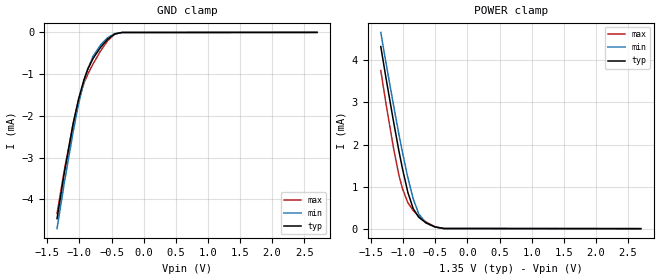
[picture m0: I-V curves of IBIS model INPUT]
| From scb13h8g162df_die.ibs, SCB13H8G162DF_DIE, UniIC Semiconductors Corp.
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|   Model INPUT
[Model] INPUT
Model_type Input
Polarity   Non-Inverting
Enable   Active-High
Vinl =  0.550V
Vinh =  0.800V
C_comp   0.556pF   0.548pF   0.561pF
C_comp_power_clamp   0.119pF   0.115pF   0.122pF
C_comp_gnd_clamp   0.437pF   0.433pF   0.439pF
[Temperature Range]   45.000   95.000   -40.000
[Voltage Range]   1.350V   1.283V   1.425V
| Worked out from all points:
|   GND clamp passes 1 mA (typ) near -0.90 V on its own axis
|   POWER clamp passes 1 mA (typ) near -0.95 V on its own axis
[GND_clamp]
|Voltage   I(typ)   I(min)   I(max)
-1.35V    -4.459mA   -4.699mA   -4.332mA
-1.238V   -3.374mA   -3.617mA   -3.314mA
-1.097V   -2.175mA   -2.364mA   -2.167mA
-1.013V   -1.587mA   -1.704mA   -1.607mA
-928mV    -1.122mA   -1.16mA    -1.204mA
-872mV    -885.7uA   -877.9uA   -1.006mA
-788mV    -622.5uA   -570.5uA   -752.1uA
-675mV    -364.9uA   -305.9uA   -453.3uA
-563mV    -165.4uA   -128.1uA   -202.9uA
-450mV    -38.09uA   -27.42uA   -40.32uA
-338mV    -2.553uA   -2.201uA   -1.39uA
2.7V      0A         0A         0A
[POWER_clamp]
|Voltage   I(typ)   I(min)   I(max)
-1.35V    4.331mA    4.667mA    3.761mA
-1.266V   3.557mA    3.918mA    2.946mA
-1.153V   2.561mA    2.949mA    1.928mA
-1.069V   1.859mA    2.255mA    1.281mA
-1.012V   1.425mA    1.815mA    950.8uA
-928mV    862.1uA    1.21mA     617uA
-844mV    472.4uA    705.3uA    428.3uA
-759mV    272.3uA    354.4uA    298.8uA
-647mV    139.8uA    137.3uA    161uA
-506mV    42.4uA     36.88uA    42.07uA
-366mV    3.748uA    3.583uA    1.942uA
2.7V      0A         0A         0A
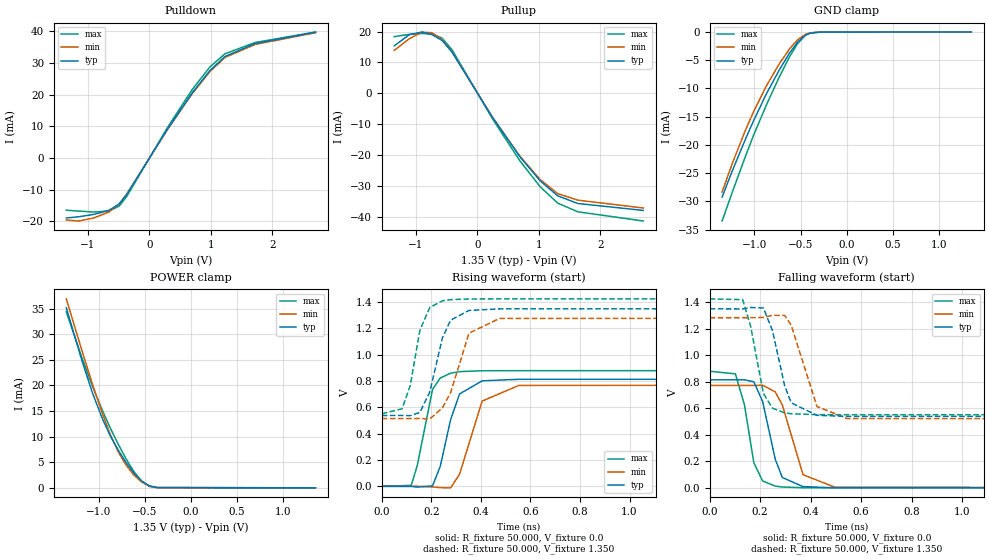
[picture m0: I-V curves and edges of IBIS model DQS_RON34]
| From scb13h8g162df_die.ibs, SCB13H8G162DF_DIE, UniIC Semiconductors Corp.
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|   Model DQS_RON34
[Model] DQS_RON34
Model_type I/O
Polarity   Non-Inverting
Enable   Active-High
Vinl =  0.545V
Vinh =  0.805V
Vmeas =  0.675V
Cref =  0.0F
Rref =  50.000
Vref =  0.675V
C_comp   0.955pF   0.936pF   0.968pF
C_comp_pullup   0.230pF   0.220pF   0.237pF
C_comp_pulldown   0.725pF   0.716pF   0.731pF
[Temperature Range]   45.000   95.000   -40.000
[Voltage Range]   1.350V   1.283V   1.425V
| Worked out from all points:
|   slope of the pulldown table from 0 to 0.203 V, typ, clamps not added: 32.2 ohm
|   slope of the pullup table from 0 to 0.203 V, typ, clamps not added: 31.7 ohm
|   GND clamp passes 1 mA (typ) near -0.48 V on its own axis
|   POWER clamp passes 1 mA (typ) near -0.51 V on its own axis
|   rising waveform, R_fixture 50.000, V_fixture 0.0: 20-80 % time 62.9ps typ, 70.8ps min, 52.9ps max; typ from 0 V to 0.814 V
|   rising waveform, R_fixture 50.000, V_fixture 1.350: 20-80 % time 65.7ps typ, 75.8ps min, 54.2ps max; typ from 0.539 V to 1.35 V
|   falling waveform, R_fixture 50.000, V_fixture 0.0: 20-80 % time 58.1ps typ, 66.1ps min, 48.7ps max; typ from 0.814 V to 0 V
|   falling waveform, R_fixture 50.000, V_fixture 1.350: 20-80 % time 60ps typ, 67.7ps min, 52ps max; typ from 1.35 V to 0.539 V
[Pulldown]
|Voltage   I(typ)   I(min)   I(max)
-1.35V    -19.01mA   -19.65mA   -16.56mA
-1.145V   -18.62mA   -19.97mA   -16.83mA
-900mV    -17.87mA   -18.99mA   -17.14mA
-655mV    -16.56mA   -17.08mA   -16.79mA
-491mV    -14.58mA   -14.62mA   -15.27mA
-368mV    -11.59mA   -11.44mA   -12.21mA
286mV     8.844mA    8.714mA    9.336mA
695mV     20.54mA    20.28mA    21.58mA
982mV     27.56mA    27.26mA    28.72mA
1.227V    32.07mA    31.76mA    32.93mA
1.718V    36.19mA    35.89mA    36.51mA
2.7V      39.79mA    39.61mA    39.83mA
[Pullup]
|Voltage   I(typ)   I(min)   I(max)
-1.35V    15.36mA    13.9mA     18.35mA
-1.105V   18.99mA    17.66mA    19.08mA
-900mV    19.84mA    19.78mA    19.37mA
-736mV    19mA       19.61mA    19.18mA
-573mV    17.13mA    17.44mA    17.89mA
-409mV    13.34mA    13.36mA    14.07mA
245mV     -7.732mA   -7.686mA   -8.189mA
695mV     -20.62mA   -20.42mA   -21.94mA
1.023V    -28.37mA   -27.97mA   -30.29mA
1.309V    -33.24mA   -32.51mA   -35.61mA
1.636V    -35.71mA   -34.63mA   -38.4mA
2.7V      -37.95mA   -37.16mA   -41.38mA
[GND_clamp]
|Voltage   I(typ)   I(min)   I(max)
-1.35V    -29.26mA   -28.34mA   -33.49mA
-1.238V   -24.53mA   -23.21mA   -28.3mA
-1.097V   -18.99mA   -17.39mA   -22.02mA
-1.013V   -15.85mA   -14.25mA   -18.44mA
-872mV    -11.01mA   -9.597mA   -12.98mA
-731mV    -6.729mA   -5.642mA   -7.982mA
-619mV    -3.711mA   -2.975mA   -4.366mA
-534mV    -1.839mA   -1.403mA   -2.088mA
-450mV    -579.7uA   -428.9uA   -569.3uA
-394mV    -185.5uA   -144.2uA   -144.2uA
-281mV    -9.318uA   -9.811uA   -3.103uA
1.35V     0A         0A         0A
[POWER_clamp]
|Voltage   I(typ)   I(min)   I(max)
-1.35V    35.16mA    36.91mA    34.39mA
-1.181V   24.89mA    26.83mA    25.44mA
-1.069V   18.67mA    20.39mA    19.96mA
-956mV    13.38mA    14.37mA    15mA
-872mV    10.11mA    10.36mA    11.63mA
-787mV    7.358mA    7.025mA    8.526mA
-703mV    4.977mA    4.465mA    5.69mA
-619mV    2.933mA    2.534mA    3.219mA
-534mV    1.338mA    1.137mA    1.316mA
-450mV    385.5uA    342uA      284.3uA
-366mV    62.9uA     66.43uA    27.04uA
1.35V     0A         0A         9.135nA
[Ramp]
| variable   typ   min   max
dV/dt_r   0.489/62.977p   0.463/70.903p   0.528/52.483p
dV/dt_f   0.487/60.040p   0.461/68.197p   0.524/51.945p
R_load = 50.000
[Rising Waveform]
R_fixture= 50.000
V_fixture= 0.0
V_fixture_min= 0.0
V_fixture_max= 0.0
|time   V(typ)   V(min)   V(max)
0s        96.21nV    255.9nV    9.828uV
119ps     -439.2uV   -70.9uV    7.242mV
143ps     -5.912mV   325.2uV    155.7mV
205ps     3.96mV     -4.63mV    737.4mV
236ps     151.3mV    -10.16mV   823mV
278ps     507.5mV    -11.58mV   860.4mV
314ps     702.2mV    92.24mV    871.8mV
405ps     801.8mV    647.9mV    878.6mV
553ps     813.7mV    767.1mV    879.4mV
5ns       814.2mV    772.4mV    879.4mV
[Rising Waveform]
R_fixture= 50.000
V_fixture= 1.350
V_fixture_min= 1.283
V_fixture_max= 1.425
|time   V(typ)   V(min)   V(max)
0s        538.6mV    515.3mV    551.5mV
82ps      538.7mV    515.3mV    589.4mV
115ps     537.1mV    515.3mV    766.7mV
154ps     562mV      515.7mV    1.187V
194ps     718mV      512.2mV    1.36V
245ps     1.13V      597mV      1.41V
278ps     1.263V     712.2mV    1.419V
352ps     1.337V     1.164V     1.424V
475ps     1.349V     1.276V     1.425V
5ns       1.35V      1.283V     1.425V
[Falling Waveform]
R_fixture= 50.000
V_fixture= 0.0
V_fixture_min= 0.0
V_fixture_max= 0.0
|time   V(typ)   V(min)   V(max)
0s        814.2mV    772.4mV    879.4mV
102ps     814.3mV    772.4mV    859.3mV
138ps     814.4mV    772.4mV    625.4mV
175ps     799.5mV    772.1mV    189.7mV
210ps     650.8mV    774.1mV    51.48mV
260ps     214.6mV    723.2mV    13.04mV
288ps     78.18mV    624.5mV    6.39mV
370ps     9.051mV    99.09mV    899.1uV
496ps     564.3uV    4.591mV    47.18uV
5ns       98.67nV    255.9nV    10.17uV
[Falling Waveform]
R_fixture= 50.000
V_fixture= 1.350
V_fixture_min= 1.283
V_fixture_max= 1.425
|time   V(typ)   V(min)   V(max)
0s        1.35V      1.283V     1.425V
131ps     1.349V     1.283V     1.419V
162ps     1.36V      1.283V     1.221V
213ps     1.356V     1.285V     710.9mV
249ps     1.185V     1.301V     601mV
297ps     771.6mV    1.3V       565.3mV
323ps     641.3mV    1.227V     558.6mV
425ps     546.7mV    613.8mV    552mV
543ps     539.3mV    522.9mV    551.5mV
5ns       538.6mV    515.3mV    551.5mV
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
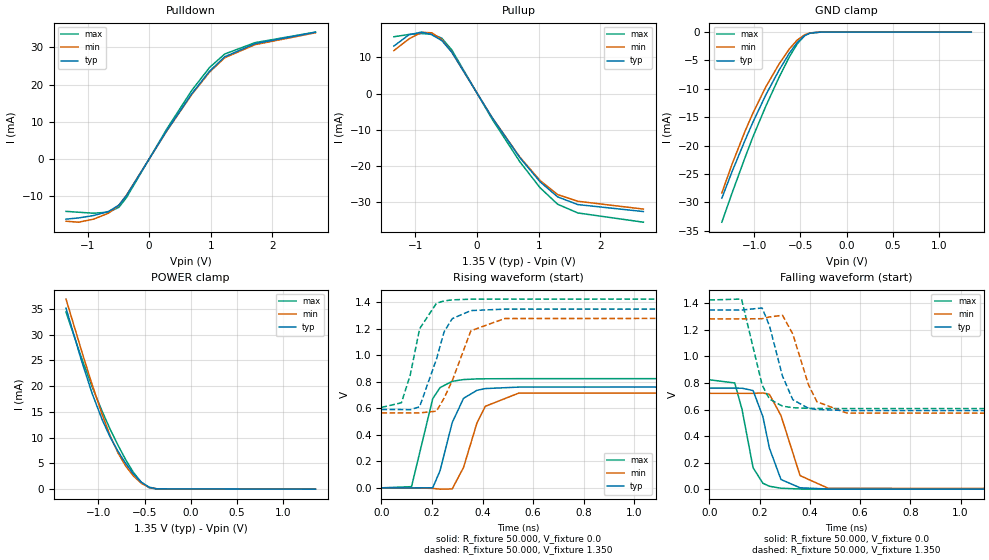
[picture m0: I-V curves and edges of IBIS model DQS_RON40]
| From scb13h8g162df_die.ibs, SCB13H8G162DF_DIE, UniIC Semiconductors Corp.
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|   Model DQS_RON40
[Model] DQS_RON40
Model_type I/O
Polarity   Non-Inverting
Enable   Active-High
Vinl =  0.545V
Vinh =  0.805V
Vmeas =  0.675V
Cref =  0.0F
Rref =  50.000
Vref =  0.675V
C_comp   0.962pF   0.943pF   0.974pF
C_comp_pullup   0.232pF   0.222pF   0.238pF
C_comp_pulldown   0.730pF   0.721pF   0.736pF
[Temperature Range]   45.000   95.000   -40.000
[Voltage Range]   1.350V   1.283V   1.425V
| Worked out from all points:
|   slope of the pulldown table from 0 to 0.203 V, typ, clamps not added: 37.6 ohm
|   slope of the pullup table from 0 to 0.203 V, typ, clamps not added: 36.9 ohm
|   GND clamp passes 1 mA (typ) near -0.48 V on its own axis
|   POWER clamp passes 1 mA (typ) near -0.51 V on its own axis
|   rising waveform, R_fixture 50.000, V_fixture 0.0: 20-80 % time 66.8ps typ, 75.1ps min, 56.5ps max; typ from 0 V to 0.761 V
|   rising waveform, R_fixture 50.000, V_fixture 1.350: 20-80 % time 71.2ps typ, 82.6ps min, 59.3ps max; typ from 0.591 V to 1.35 V
|   falling waveform, R_fixture 50.000, V_fixture 0.0: 20-80 % time 58.8ps typ, 68.9ps min, 50.6ps max; typ from 0.761 V to 0 V
|   falling waveform, R_fixture 50.000, V_fixture 1.350: 20-80 % time 66.4ps typ, 74.8ps min, 57.3ps max; typ from 1.35 V to 0.591 V
[Pulldown]
|Voltage   I(typ)   I(min)   I(max)
-1.35V    -16.29mA   -16.85mA   -14.19mA
-1.145V   -15.96mA   -17.11mA   -14.43mA
-900mV    -15.31mA   -16.28mA   -14.69mA
-655mV    -14.19mA   -14.64mA   -14.39mA
-491mV    -12.5mA    -12.53mA   -13.09mA
-368mV    -9.933mA   -9.802mA   -10.47mA
286mV     7.58mA     7.47mA     8.003mA
695mV     17.6mA     17.38mA    18.5mA
982mV     23.62mA    23.37mA    24.62mA
1.227V    27.49mA    27.22mA    28.23mA
1.718V    31.02mA    30.75mA    31.29mA
2.7V      34.1mA     33.95mA    34.14mA
[Pullup]
|Voltage   I(typ)   I(min)   I(max)
-1.35V    13.16mA    11.91mA    15.72mA
-1.105V   16.28mA    15.14mA    16.36mA
-900mV    17.01mA    16.95mA    16.6mA
-736mV    16.29mA    16.81mA    16.44mA
-573mV    14.68mA    14.95mA    15.34mA
-409mV    11.44mA    11.45mA    12.06mA
245mV     -6.628mA   -6.587mA   -7.019mA
695mV     -17.68mA   -17.5mA    -18.8mA
1.023V    -24.32mA   -23.97mA   -25.96mA
1.309V    -28.49mA   -27.86mA   -30.52mA
1.636V    -30.61mA   -29.69mA   -32.92mA
2.7V      -32.53mA   -31.85mA   -35.47mA
[GND_clamp]
|Voltage   I(typ)   I(min)   I(max)
-1.35V    -29.26mA   -28.34mA   -33.49mA
-1.238V   -24.53mA   -23.21mA   -28.3mA
-1.097V   -18.99mA   -17.39mA   -22.02mA
-1.013V   -15.85mA   -14.25mA   -18.44mA
-872mV    -11.01mA   -9.597mA   -12.98mA
-731mV    -6.729mA   -5.642mA   -7.982mA
-619mV    -3.711mA   -2.975mA   -4.366mA
-534mV    -1.839mA   -1.403mA   -2.088mA
-450mV    -579.7uA   -428.9uA   -569.3uA
-394mV    -185.5uA   -144.2uA   -144.2uA
-281mV    -9.318uA   -9.811uA   -3.103uA
1.35V     0A         0A         0A
[POWER_clamp]
|Voltage   I(typ)   I(min)   I(max)
-1.35V    35.16mA    36.91mA    34.39mA
-1.181V   24.89mA    26.83mA    25.44mA
-1.069V   18.67mA    20.39mA    19.96mA
-956mV    13.38mA    14.37mA    15mA
-872mV    10.11mA    10.36mA    11.63mA
-787mV    7.358mA    7.025mA    8.526mA
-703mV    4.977mA    4.465mA    5.69mA
-619mV    2.933mA    2.534mA    3.219mA
-534mV    1.338mA    1.137mA    1.316mA
-450mV    385.5uA    342uA      284.3uA
-366mV    62.9uA     66.43uA    27.04uA
1.35V     0A         0A         9.135nA
[Ramp]
| variable   typ   min   max
dV/dt_r   0.457/67.068p   0.433/75.437p   0.494/56.454p
dV/dt_f   0.455/66.331p   0.431/74.640p   0.491/58.220p
R_load = 50.000
[Rising Waveform]
R_fixture= 50.000
V_fixture= 0.0
V_fixture_min= 0.0
V_fixture_max= 0.0
|time   V(typ)   V(min)   V(max)
0s        104.4nV    279.9nV    10.03uV
119ps     -364.1uV   -73.9uV    8.881mV
203ps     464.6uV    -4.308mV   673.4mV
232ps     129.5mV    -10.12mV   756.8mV
280ps     492mV      -8.598mV   804mV
325ps     676mV      154.5mV    817.3mV
378ps     736.2mV    489.8mV    822.1mV
411ps     749.3mV    615.4mV    823.2mV
543ps     760.4mV    714.7mV    824mV
5ns       761.1mV    722mV      824mV
[Rising Waveform]
R_fixture= 50.000
V_fixture= 1.350
V_fixture_min= 1.283
V_fixture_max= 1.425
|time   V(typ)   V(min)   V(max)
0s        591.3mV    565.2mV    607mV
79ps      591.3mV    565.2mV    642mV
114ps     589.6mV    565.2mV    851.1mV
151ps     611.7mV    565.6mV    1.201V
218ps     972.9mV    578.8mV    1.394V
248ps     1.178V     677.4mV    1.411V
280ps     1.277V     808.1mV    1.419V
354ps     1.338V     1.186V     1.424V
488ps     1.349V     1.278V     1.425V
5ns       1.35V      1.283V     1.425V
[Falling Waveform]
R_fixture= 50.000
V_fixture= 0.0
V_fixture_min= 0.0
V_fixture_max= 0.0
|time   V(typ)   V(min)   V(max)
0s        761.1mV    722mV      824mV
101ps     761.2mV    722mV      799.9mV
130ps     760.5mV    722mV      600.8mV
174ps     742.8mV    721.6mV    161.5mV
213ps     546.3mV    724.5mV    44.51mV
239ps     309mV      714.3mV    21.87mV
285ps     72.74mV    554.5mV    7.154mV
361ps     10.55mV    102.2mV    1.212mV
473ps     917.5uV    6.806mV    89.78uV
5ns       106.7nV    279.9nV    9.968uV
[Falling Waveform]
R_fixture= 50.000
V_fixture= 1.350
V_fixture_min= 1.283
V_fixture_max= 1.425
|time   V(typ)   V(min)   V(max)
0s        1.35V      1.283V     1.425V
128ps     1.349V     1.283V     1.432V
210ps     1.365V     1.284V     785mV
239ps     1.232V     1.297V     679.3mV
291ps     852mV      1.31V      625.4mV
332ps     674mV      1.169V     613.8mV
394ps     609.7mV    788.5mV    608.5mV
428ps     600mV      659.2mV    607.7mV
546ps     592mV      573.5mV    607mV
5ns       591.3mV    565.2mV    607mV
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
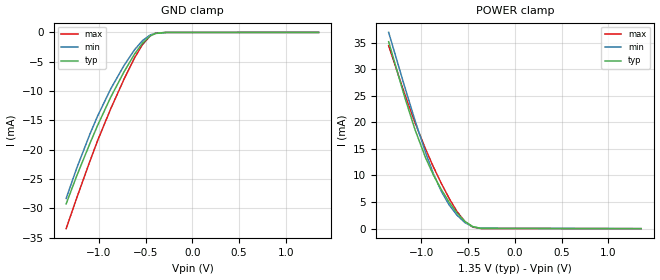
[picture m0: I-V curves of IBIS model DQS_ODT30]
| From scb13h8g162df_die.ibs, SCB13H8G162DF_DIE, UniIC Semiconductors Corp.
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|   Model DQS_ODT30
[Model] DQS_ODT30
Model_type Input
Polarity   Non-Inverting
Enable   Active-High
Vinl =  0.545V
Vinh =  0.805V
C_comp   0.986pF   0.969pF   0.995pF
C_comp_power_clamp   0.234pF   0.227pF   0.238pF
C_comp_gnd_clamp   0.752pF   0.742pF   0.757pF
[Add Submodel]
|  Submodel_name   Mode
DQS_30ohm_ODT   Non-Driving
[Temperature Range]   45.000   95.000   -40.000
[Voltage Range]   1.350V   1.283V   1.425V
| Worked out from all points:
|   GND clamp passes 1 mA (typ) near -0.48 V on its own axis
|   POWER clamp passes 1 mA (typ) near -0.51 V on its own axis
[GND_clamp]
|Voltage   I(typ)   I(min)   I(max)
-1.35V    -29.26mA   -28.34mA   -33.49mA
-1.238V   -24.53mA   -23.21mA   -28.3mA
-1.097V   -18.99mA   -17.39mA   -22.02mA
-1.013V   -15.85mA   -14.25mA   -18.44mA
-872mV    -11.01mA   -9.597mA   -12.98mA
-731mV    -6.729mA   -5.642mA   -7.982mA
-619mV    -3.711mA   -2.975mA   -4.366mA
-534mV    -1.839mA   -1.403mA   -2.088mA
-450mV    -579.7uA   -428.9uA   -569.3uA
-394mV    -185.5uA   -144.2uA   -144.2uA
-281mV    -9.318uA   -9.811uA   -3.103uA
1.35V     0A         0A         0A
[POWER_clamp]
|Voltage   I(typ)   I(min)   I(max)
-1.35V    35.16mA    36.91mA    34.39mA
-1.181V   24.89mA    26.83mA    25.44mA
-1.069V   18.67mA    20.39mA    19.96mA
-956mV    13.38mA    14.37mA    15mA
-872mV    10.11mA    10.36mA    11.63mA
-787mV    7.358mA    7.025mA    8.526mA
-703mV    4.977mA    4.465mA    5.69mA
-619mV    2.933mA    2.534mA    3.219mA
-534mV    1.338mA    1.137mA    1.316mA
-450mV    385.5uA    342uA      284.3uA
-366mV    62.9uA     66.43uA    27.04uA
1.35V     0A         0A         9.135nA
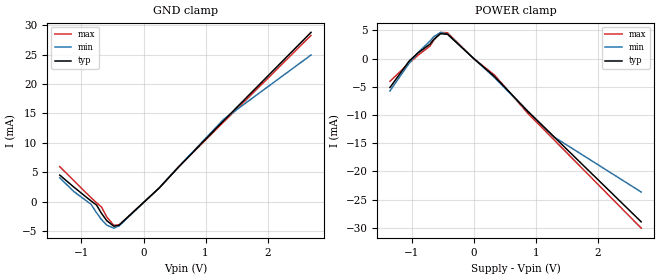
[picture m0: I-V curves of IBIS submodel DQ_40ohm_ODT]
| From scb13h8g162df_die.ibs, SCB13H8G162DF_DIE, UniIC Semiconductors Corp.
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|   Submodel DQ_40ohm_ODT
[Submodel] DQ_40ohm_ODT
Submodel_type Dynamic_clamp
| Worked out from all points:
|   GND clamp passes 1 mA (typ) near -0.09 V on its own axis
|   POWER clamp passes 1 mA (typ) near -0.09 V on its own axis
[GND_clamp]
|Voltage   I(typ)   I(min)   I(max)
-1.35V    4.509mA    4.048mA    5.947mA
-1.125V   2.483mA    1.728mA    3.581mA
-844mV    92.4uA     -476.4uA   643.2uA
-759mV    -570.5uA   -1.863mA   -173.5uA
-675mV    -2.029mA   -3.082mA   -952.5uA
-591mV    -3.257mA   -4.013mA   -2.635mA
-478mV    -4.184mA   -4.515mA   -4.045mA
-394mV    -4.011mA   -4.131mA   -3.979mA
253mV     2.318mA    2.343mA    2.291mA
562mV     5.83mA     5.869mA    5.89mA
1.294V    13.79mA    14.02mA    13.55mA
2.7V      28.78mA    24.93mA    28.27mA
[POWER_clamp]
|Voltage   I(typ)   I(min)   I(max)
-1.35V    -5.144mA   -5.742mA   -4.038mA
-1.041V   -450.5uA   -846.7uA   -805.3uA
-900mV    972.2uA    1.024mA    559.9uA
-703mV    2.555mA    3.099mA    2.211mA
-647mV    3.357mA    3.841mA    3.205mA
-534mV    4.386mA    4.612mA    4.629mA
-422mV    4.296mA    4.332mA    4.553mA
100nV     -189.3nA   -185nA     -197.2nA
338mV     -3.204mA   -3.405mA   -2.957mA
872mV     -9.339mA   -9.379mA   -9.701mA
1.294V    -13.86mA   -13.89mA   -14.39mA
2.7V      -28.92mA   -23.64mA   -30.04mA
